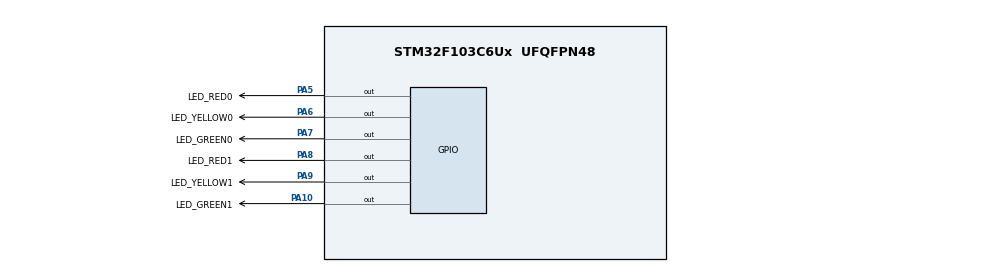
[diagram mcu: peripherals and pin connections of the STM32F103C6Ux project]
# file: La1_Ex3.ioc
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Mcu.Family=STM32F1
Mcu.Name=STM32F103C6Ux
Mcu.Package=UFQFPN48
NVIC.PriorityGroup=NVIC_PRIORITYGROUP_4
PA10.GPIO_Label=LED_GREEN1
PA10.Signal=GPIO_Output
PA5.GPIO_Label=LED_RED0
PA5.Signal=GPIO_Output
PA6.GPIO_Label=LED_YELLOW0
PA6.Signal=GPIO_Output
PA7.GPIO_Label=LED_GREEN0
PA7.Signal=GPIO_Output
PA8.GPIO_Label=LED_RED1
PA8.Signal=GPIO_Output
PA9.GPIO_Label=LED_YELLOW1
PA9.Signal=GPIO_Output
ProjectManager.HeapSize=0x200
ProjectManager.StackSize=0x400
ProjectManager.TargetToolchain=STM32CubeIDE
RCC.SYSCLKSource=RCC_SYSCLKSOURCE_PLLCLK
board=custom

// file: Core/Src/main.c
/* USER CODE BEGIN Header */
/**
  ******************************************************************************
  * @file           : main.c
  * @brief          : Main program body
  ******************************************************************************
  * @attention
  *
  * Copyright (c) 2022 STMicroelectronics.
  * All rights reserved.
  *
  * This software is licensed under terms that can be found in the LICENSE file
  * in the root directory of this software component.
  * If no LICENSE file comes with this software, it is provided AS-IS.
  *
  ******************************************************************************
  */
/* USER CODE END Header */
#include "main.h"

void SystemClock_Config(void);
static void MX_GPIO_Init(void);

int main(void)
{

  /* MCU Configuration--------------------------------------------------------*/

  /* Reset of all peripherals, Initializes the Flash interface and the Systick. */
  HAL_Init();

  /* Configure the system clock */
  SystemClock_Config();

  /* Initialize all configured peripherals */
  MX_GPIO_Init();

  /* Infinite loop */
  /* USER CODE BEGIN WHILE */
  int counter =0;
  while (1)
  {if (counter ==10) {
		counter = 0;}

	  if (counter>=0 && counter <2 ){
		  HAL_GPIO_WritePin(LED_YELLOW1_GPIO_Port, LED_YELLOW1_Pin, SET);
		  HAL_GPIO_WritePin(LED_RED0_GPIO_Port, LED_RED0_Pin, SET);
		  HAL_GPIO_WritePin(LED_YELLOW0_GPIO_Port, LED_YELLOW0_Pin, RESET);
		  HAL_GPIO_WritePin(LED_GREEN0_GPIO_Port, LED_GREEN0_Pin, RESET);
		  HAL_GPIO_WritePin(LED_GREEN1_GPIO_Port, LED_GREEN1_Pin, RESET);
		  HAL_GPIO_WritePin(LED_RED1_GPIO_Port, LED_RED1_Pin, RESET);
	  } if (counter>=2 && counter <5){
		  HAL_GPIO_WritePin(LED_GREEN1_GPIO_Port, LED_GREEN1_Pin, SET);
		  HAL_GPIO_WritePin(LED_RED0_GPIO_Port, LED_RED0_Pin, SET);
		  HAL_GPIO_WritePin(LED_YELLOW0_GPIO_Port, LED_YELLOW0_Pin, RESET);
		  HAL_GPIO_WritePin(LED_GREEN0_GPIO_Port, LED_GREEN0_Pin, RESET);
		  HAL_GPIO_WritePin(LED_RED1_GPIO_Port, LED_RED1_Pin, RESET);
		  HAL_GPIO_WritePin(LED_YELLOW1_GPIO_Port, LED_YELLOW1_Pin, RESET);
	  } if (counter>=5 && counter <7){
		  HAL_GPIO_WritePin(LED_YELLOW0_GPIO_Port, LED_YELLOW0_Pin, SET);
		  HAL_GPIO_WritePin(LED_RED1_GPIO_Port, LED_RED1_Pin, SET);
		  HAL_GPIO_WritePin(LED_YELLOW1_GPIO_Port, LED_YELLOW1_Pin, RESET);
		  HAL_GPIO_WritePin(LED_GREEN1_GPIO_Port, LED_GREEN1_Pin, RESET);
		  HAL_GPIO_WritePin(LED_GREEN0_GPIO_Port, LED_GREEN0_Pin, RESET);
		  HAL_GPIO_WritePin(LED_RED0_GPIO_Port, LED_RED0_Pin, RESET);
	  } if (counter>=7 && counter <10){
		  	  	  HAL_GPIO_WritePin(LED_GREEN0_GPIO_Port, LED_GREEN0_Pin, SET);
		  		  HAL_GPIO_WritePin(LED_RED1_GPIO_Port, LED_RED1_Pin, SET);
		  		  HAL_GPIO_WritePin(LED_YELLOW1_GPIO_Port, LED_YELLOW1_Pin, RESET);
		  		HAL_GPIO_WritePin(LED_GREEN1_GPIO_Port, LED_GREEN1_Pin, RESET);
		  		  HAL_GPIO_WritePin(LED_RED0_GPIO_Port, LED_RED0_Pin, RESET);
		  		  HAL_GPIO_WritePin(LED_YELLOW0_GPIO_Port, LED_YELLOW0_Pin, RESET);
	  }
    /* USER CODE END WHILE */
counter +=1;
HAL_Delay(100);
  }
}

void SystemClock_Config(void)
{
  RCC_OscInitTypeDef RCC_OscInitStruct = {0};
  RCC_ClkInitTypeDef RCC_ClkInitStruct = {0};

  /** Initializes the RCC Oscillators according to the specified parameters
  * in the RCC_OscInitTypeDef structure.
  */
  RCC_OscInitStruct.OscillatorType = RCC_OSCILLATORTYPE_HSI;
  RCC_OscInitStruct.HSIState = RCC_HSI_ON;
  RCC_OscInitStruct.HSICalibrationValue = RCC_HSICALIBRATION_DEFAULT;
  RCC_OscInitStruct.PLL.PLLState = RCC_PLL_NONE;
  if (HAL_RCC_OscConfig(&RCC_OscInitStruct) != HAL_OK)
  {
    Error_Handler();
  }

  /** Initializes the CPU, AHB and APB buses clocks
  */
  RCC_ClkInitStruct.ClockType = RCC_CLOCKTYPE_HCLK|RCC_CLOCKTYPE_SYSCLK
                              |RCC_CLOCKTYPE_PCLK1|RCC_CLOCKTYPE_PCLK2;
  RCC_ClkInitStruct.SYSCLKSource = RCC_SYSCLKSOURCE_HSI;
  RCC_ClkInitStruct.AHBCLKDivider = RCC_SYSCLK_DIV1;
  RCC_ClkInitStruct.APB1CLKDivider = RCC_HCLK_DIV1;
  RCC_ClkInitStruct.APB2CLKDivider = RCC_HCLK_DIV1;

  if (HAL_RCC_ClockConfig(&RCC_ClkInitStruct, FLASH_LATENCY_0) != HAL_OK)
  {
    Error_Handler();
  }
}

static void MX_GPIO_Init(void)
{
  GPIO_InitTypeDef GPIO_InitStruct = {0};

  /* GPIO Ports Clock Enable */
  __HAL_RCC_GPIOA_CLK_ENABLE();

  /*Configure GPIO pin Output Level */
  HAL_GPIO_WritePin(GPIOA, LED_RED0_Pin|LED_YELLOW0_Pin|LED_GREEN0_Pin|LED_RED1_Pin
                          |LED_YELLOW1_Pin|LED_GREEN1_Pin, GPIO_PIN_RESET);

  /*Configure GPIO pins : LED_RED0_Pin LED_YELLOW0_Pin LED_GREEN0_Pin LED_RED1_Pin
                           LED_YELLOW1_Pin LED_GREEN1_Pin */
  GPIO_InitStruct.Pin = LED_RED0_Pin|LED_YELLOW0_Pin|LED_GREEN0_Pin|LED_RED1_Pin
                          |LED_YELLOW1_Pin|LED_GREEN1_Pin;
  GPIO_InitStruct.Mode = GPIO_MODE_OUTPUT_PP;
  GPIO_InitStruct.Pull = GPIO_NOPULL;
  GPIO_InitStruct.Speed = GPIO_SPEED_FREQ_LOW;
  HAL_GPIO_Init(GPIOA, &GPIO_InitStruct);

}

void Error_Handler(void)
{
  __disable_irq();
  while (1)
  {
  }
}
